VERSION 5.7 ;
BUSBITCHARS "[]" ;
DIVIDERCHAR "/" ;
UNITS
  DATABASE MICRONS 1000 ;
END UNITS

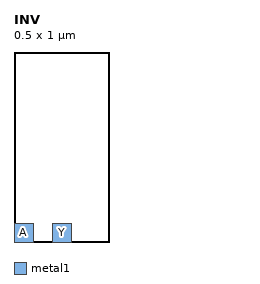
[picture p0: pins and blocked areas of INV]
MACRO INV
  CLASS CORE ;
  SIZE 0.5 BY 1.0 ;
  PIN A
    DIRECTION INPUT ;
    USE SIGNAL ;
    PORT
      LAYER metal1 ;
        RECT 0.0 0.0 0.1 0.1 ;
    END
  END A
  PIN Y
    DIRECTION OUTPUT ;
    USE SIGNAL ;
    PORT
      LAYER metal1 ;
        RECT 0.2 0.0 0.3 0.1 ;
    END
  END Y
  PIN VDD
    DIRECTION INOUT ;
    USE POWER ;
  END VDD
  PIN VSS
    DIRECTION INOUT ;
    USE GROUND ;
  END VSS
END INV

MACRO AND2
  CLASS CORE ;
  SIZE 0.8 BY 1.0 ;
  PIN A
    DIRECTION INPUT ;
    USE SIGNAL ;
  END A
  PIN B
    DIRECTION INPUT ;
    USE SIGNAL ;
  END B
  PIN Y
    DIRECTION OUTPUT ;
    USE SIGNAL ;
  END Y
END AND2

MACRO DFF
  CLASS CORE ;
  SIZE 2.0 BY 1.0 ;
  PIN D
    DIRECTION INPUT ;
    USE SIGNAL ;
  END D
  PIN CK
    DIRECTION INPUT ;
    USE CLOCK ;
  END CK
  PIN Q
    DIRECTION OUTPUT ;
    USE SIGNAL ;
  END Q
END DFF

MACRO RAM8
  CLASS BLOCK ;
  SIZE 20.0 BY 20.0 ;
  PIN CLK
    DIRECTION INPUT ;
    USE SIGNAL ;
  END CLK
  PIN ADDR
    DIRECTION INPUT ;
    USE SIGNAL ;
  END ADDR
  PIN WD
    DIRECTION INPUT ;
    USE SIGNAL ;
  END WD
  PIN RD
    DIRECTION OUTPUT ;
    USE SIGNAL ;
  END RD
END RAM8
